VERSION 5.7 ;
  NOWIREEXTENSIONATPIN ON ;
  DIVIDERCHAR "/" ;
  BUSBITCHARS "[]" ;
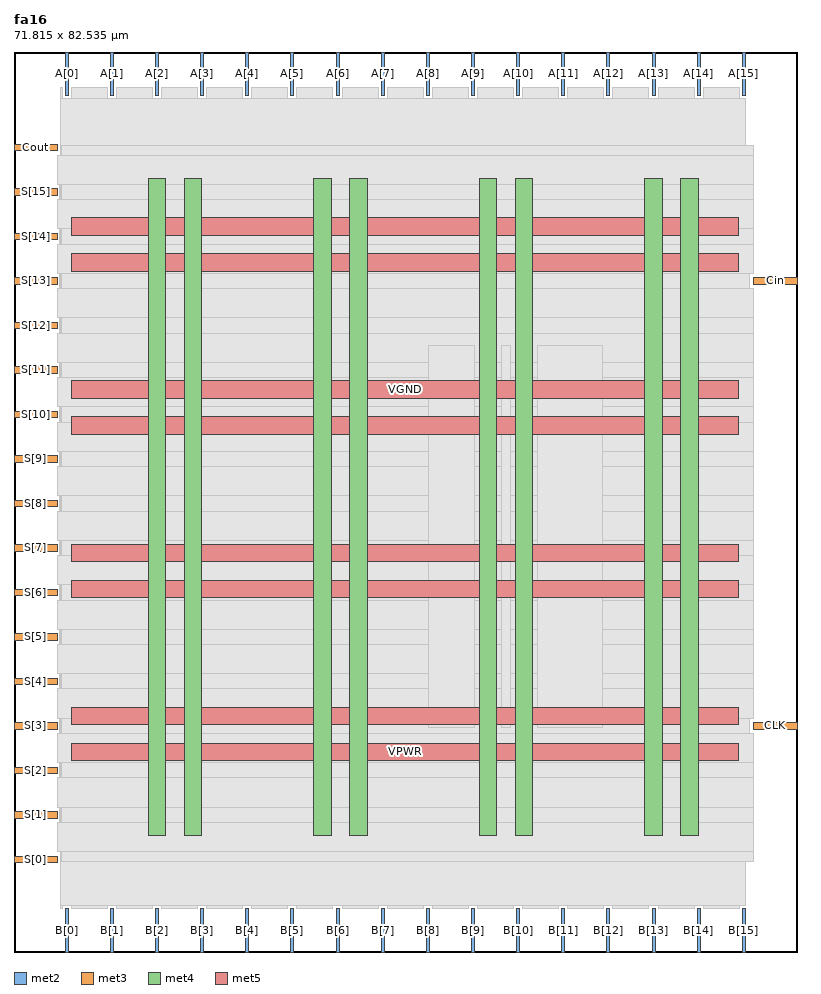
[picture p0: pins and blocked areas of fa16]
MACRO fa16
  CLASS BLOCK ;
  FOREIGN fa16 ;
  ORIGIN 0.000 0.000 ;
  SIZE 71.815 BY 82.535 ;
  PIN A[0]
    DIRECTION INPUT ;
    USE SIGNAL ;
    ANTENNAGATEAREA 0.196500 ;
    PORT
      LAYER met2 ;
        RECT 4.690 78.535 4.970 82.535 ;
    END
  END A[0]
  PIN A[10]
    DIRECTION INPUT ;
    USE SIGNAL ;
    ANTENNAGATEAREA 0.196500 ;
    PORT
      LAYER met2 ;
        RECT 46.090 78.535 46.370 82.535 ;
    END
  END A[10]
  PIN A[11]
    DIRECTION INPUT ;
    USE SIGNAL ;
    ANTENNAGATEAREA 0.196500 ;
    PORT
      LAYER met2 ;
        RECT 50.230 78.535 50.510 82.535 ;
    END
  END A[11]
  PIN A[12]
    DIRECTION INPUT ;
    USE SIGNAL ;
    ANTENNAGATEAREA 0.196500 ;
    PORT
      LAYER met2 ;
        RECT 54.370 78.535 54.650 82.535 ;
    END
  END A[12]
  PIN A[13]
    DIRECTION INPUT ;
    USE SIGNAL ;
    ANTENNAGATEAREA 0.196500 ;
    PORT
      LAYER met2 ;
        RECT 58.510 78.535 58.790 82.535 ;
    END
  END A[13]
  PIN A[14]
    DIRECTION INPUT ;
    USE SIGNAL ;
    ANTENNAGATEAREA 0.196500 ;
    PORT
      LAYER met2 ;
        RECT 62.650 78.535 62.930 82.535 ;
    END
  END A[14]
  PIN A[15]
    DIRECTION INPUT ;
    USE SIGNAL ;
    ANTENNAGATEAREA 0.196500 ;
    PORT
      LAYER met2 ;
        RECT 66.790 78.535 67.070 82.535 ;
    END
  END A[15]
  PIN A[1]
    DIRECTION INPUT ;
    USE SIGNAL ;
    ANTENNAGATEAREA 0.196500 ;
    PORT
      LAYER met2 ;
        RECT 8.830 78.535 9.110 82.535 ;
    END
  END A[1]
  PIN A[2]
    DIRECTION INPUT ;
    USE SIGNAL ;
    ANTENNAGATEAREA 0.196500 ;
    PORT
      LAYER met2 ;
        RECT 12.970 78.535 13.250 82.535 ;
    END
  END A[2]
  PIN A[3]
    DIRECTION INPUT ;
    USE SIGNAL ;
    ANTENNAGATEAREA 0.196500 ;
    PORT
      LAYER met2 ;
        RECT 17.110 78.535 17.390 82.535 ;
    END
  END A[3]
  PIN A[4]
    DIRECTION INPUT ;
    USE SIGNAL ;
    ANTENNAGATEAREA 0.196500 ;
    PORT
      LAYER met2 ;
        RECT 21.250 78.535 21.530 82.535 ;
    END
  END A[4]
  PIN A[5]
    DIRECTION INPUT ;
    USE SIGNAL ;
    ANTENNAGATEAREA 0.196500 ;
    PORT
      LAYER met2 ;
        RECT 25.390 78.535 25.670 82.535 ;
    END
  END A[5]
  PIN A[6]
    DIRECTION INPUT ;
    USE SIGNAL ;
    ANTENNAGATEAREA 0.196500 ;
    PORT
      LAYER met2 ;
        RECT 29.530 78.535 29.810 82.535 ;
    END
  END A[6]
  PIN A[7]
    DIRECTION INPUT ;
    USE SIGNAL ;
    ANTENNAGATEAREA 0.196500 ;
    PORT
      LAYER met2 ;
        RECT 33.670 78.535 33.950 82.535 ;
    END
  END A[7]
  PIN A[8]
    DIRECTION INPUT ;
    USE SIGNAL ;
    ANTENNAGATEAREA 0.196500 ;
    PORT
      LAYER met2 ;
        RECT 37.810 78.535 38.090 82.535 ;
    END
  END A[8]
  PIN A[9]
    DIRECTION INPUT ;
    USE SIGNAL ;
    ANTENNAGATEAREA 0.196500 ;
    PORT
      LAYER met2 ;
        RECT 41.950 78.535 42.230 82.535 ;
    END
  END A[9]
  PIN B[0]
    DIRECTION INPUT ;
    USE SIGNAL ;
    ANTENNAGATEAREA 0.196500 ;
    PORT
      LAYER met2 ;
        RECT 4.690 0.000 4.970 4.000 ;
    END
  END B[0]
  PIN B[10]
    DIRECTION INPUT ;
    USE SIGNAL ;
    ANTENNAGATEAREA 0.196500 ;
    PORT
      LAYER met2 ;
        RECT 46.090 0.000 46.370 4.000 ;
    END
  END B[10]
  PIN B[11]
    DIRECTION INPUT ;
    USE SIGNAL ;
    ANTENNAGATEAREA 0.196500 ;
    PORT
      LAYER met2 ;
        RECT 50.230 0.000 50.510 4.000 ;
    END
  END B[11]
  PIN B[12]
    DIRECTION INPUT ;
    USE SIGNAL ;
    ANTENNAGATEAREA 0.196500 ;
    PORT
      LAYER met2 ;
        RECT 54.370 0.000 54.650 4.000 ;
    END
  END B[12]
  PIN B[13]
    DIRECTION INPUT ;
    USE SIGNAL ;
    ANTENNAGATEAREA 0.196500 ;
    PORT
      LAYER met2 ;
        RECT 58.510 0.000 58.790 4.000 ;
    END
  END B[13]
  PIN B[14]
    DIRECTION INPUT ;
    USE SIGNAL ;
    ANTENNAGATEAREA 0.196500 ;
    PORT
      LAYER met2 ;
        RECT 62.650 0.000 62.930 4.000 ;
    END
  END B[14]
  PIN B[15]
    DIRECTION INPUT ;
    USE SIGNAL ;
    ANTENNAGATEAREA 0.196500 ;
    PORT
      LAYER met2 ;
        RECT 66.790 0.000 67.070 4.000 ;
    END
  END B[15]
  PIN B[1]
    DIRECTION INPUT ;
    USE SIGNAL ;
    ANTENNAGATEAREA 0.196500 ;
    PORT
      LAYER met2 ;
        RECT 8.830 0.000 9.110 4.000 ;
    END
  END B[1]
  PIN B[2]
    DIRECTION INPUT ;
    USE SIGNAL ;
    ANTENNAGATEAREA 0.196500 ;
    PORT
      LAYER met2 ;
        RECT 12.970 0.000 13.250 4.000 ;
    END
  END B[2]
  PIN B[3]
    DIRECTION INPUT ;
    USE SIGNAL ;
    ANTENNAGATEAREA 0.196500 ;
    PORT
      LAYER met2 ;
        RECT 17.110 0.000 17.390 4.000 ;
    END
  END B[3]
  PIN B[4]
    DIRECTION INPUT ;
    USE SIGNAL ;
    ANTENNAGATEAREA 0.196500 ;
    PORT
      LAYER met2 ;
        RECT 21.250 0.000 21.530 4.000 ;
    END
  END B[4]
  PIN B[5]
    DIRECTION INPUT ;
    USE SIGNAL ;
    ANTENNAGATEAREA 0.196500 ;
    PORT
      LAYER met2 ;
        RECT 25.390 0.000 25.670 4.000 ;
    END
  END B[5]
  PIN B[6]
    DIRECTION INPUT ;
    USE SIGNAL ;
    ANTENNAGATEAREA 0.196500 ;
    PORT
      LAYER met2 ;
        RECT 29.530 0.000 29.810 4.000 ;
    END
  END B[6]
  PIN B[7]
    DIRECTION INPUT ;
    USE SIGNAL ;
    ANTENNAGATEAREA 0.196500 ;
    PORT
      LAYER met2 ;
        RECT 33.670 0.000 33.950 4.000 ;
    END
  END B[7]
  PIN B[8]
    DIRECTION INPUT ;
    USE SIGNAL ;
    ANTENNAGATEAREA 0.196500 ;
    PORT
      LAYER met2 ;
        RECT 37.810 0.000 38.090 4.000 ;
    END
  END B[8]
  PIN B[9]
    DIRECTION INPUT ;
    USE SIGNAL ;
    ANTENNAGATEAREA 0.196500 ;
    PORT
      LAYER met2 ;
        RECT 41.950 0.000 42.230 4.000 ;
    END
  END B[9]
  PIN CLK
    DIRECTION INPUT ;
    USE SIGNAL ;
    ANTENNAGATEAREA 0.852000 ;
    PORT
      LAYER met3 ;
        RECT 67.815 20.440 71.815 21.040 ;
    END
  END CLK
  PIN Cin
    DIRECTION INPUT ;
    USE SIGNAL ;
    ANTENNAGATEAREA 0.196500 ;
    PORT
      LAYER met3 ;
        RECT 67.815 61.240 71.815 61.840 ;
    END
  END Cin
  PIN Cout
    DIRECTION OUTPUT ;
    USE SIGNAL ;
    ANTENNADIFFAREA 0.340600 ;
    PORT
      LAYER met3 ;
        RECT 0.000 73.480 4.000 74.080 ;
    END
  END Cout
  PIN S[0]
    DIRECTION OUTPUT ;
    USE SIGNAL ;
    ANTENNADIFFAREA 0.340600 ;
    PORT
      LAYER met3 ;
        RECT 0.000 8.200 4.000 8.800 ;
    END
  END S[0]
  PIN S[10]
    DIRECTION OUTPUT ;
    USE SIGNAL ;
    ANTENNADIFFAREA 0.340600 ;
    PORT
      LAYER met3 ;
        RECT 0.000 49.000 4.000 49.600 ;
    END
  END S[10]
  PIN S[11]
    DIRECTION OUTPUT ;
    USE SIGNAL ;
    ANTENNADIFFAREA 0.340600 ;
    PORT
      LAYER met3 ;
        RECT 0.000 53.080 4.000 53.680 ;
    END
  END S[11]
  PIN S[12]
    DIRECTION OUTPUT ;
    USE SIGNAL ;
    ANTENNADIFFAREA 0.340600 ;
    PORT
      LAYER met3 ;
        RECT 0.000 57.160 4.000 57.760 ;
    END
  END S[12]
  PIN S[13]
    DIRECTION OUTPUT ;
    USE SIGNAL ;
    ANTENNADIFFAREA 0.340600 ;
    PORT
      LAYER met3 ;
        RECT 0.000 61.240 4.000 61.840 ;
    END
  END S[13]
  PIN S[14]
    DIRECTION OUTPUT ;
    USE SIGNAL ;
    ANTENNADIFFAREA 0.340600 ;
    PORT
      LAYER met3 ;
        RECT 0.000 65.320 4.000 65.920 ;
    END
  END S[14]
  PIN S[15]
    DIRECTION OUTPUT ;
    USE SIGNAL ;
    ANTENNADIFFAREA 0.340600 ;
    PORT
      LAYER met3 ;
        RECT 0.000 69.400 4.000 70.000 ;
    END
  END S[15]
  PIN S[1]
    DIRECTION OUTPUT ;
    USE SIGNAL ;
    ANTENNADIFFAREA 0.340600 ;
    PORT
      LAYER met3 ;
        RECT 0.000 12.280 4.000 12.880 ;
    END
  END S[1]
  PIN S[2]
    DIRECTION OUTPUT ;
    USE SIGNAL ;
    ANTENNADIFFAREA 0.340600 ;
    PORT
      LAYER met3 ;
        RECT 0.000 16.360 4.000 16.960 ;
    END
  END S[2]
  PIN S[3]
    DIRECTION OUTPUT ;
    USE SIGNAL ;
    ANTENNADIFFAREA 0.340600 ;
    PORT
      LAYER met3 ;
        RECT 0.000 20.440 4.000 21.040 ;
    END
  END S[3]
  PIN S[4]
    DIRECTION OUTPUT ;
    USE SIGNAL ;
    ANTENNADIFFAREA 0.340600 ;
    PORT
      LAYER met3 ;
        RECT 0.000 24.520 4.000 25.120 ;
    END
  END S[4]
  PIN S[5]
    DIRECTION OUTPUT ;
    USE SIGNAL ;
    ANTENNADIFFAREA 0.340600 ;
    PORT
      LAYER met3 ;
        RECT 0.000 28.600 4.000 29.200 ;
    END
  END S[5]
  PIN S[6]
    DIRECTION OUTPUT ;
    USE SIGNAL ;
    ANTENNADIFFAREA 0.340600 ;
    PORT
      LAYER met3 ;
        RECT 0.000 32.680 4.000 33.280 ;
    END
  END S[6]
  PIN S[7]
    DIRECTION OUTPUT ;
    USE SIGNAL ;
    ANTENNADIFFAREA 0.340600 ;
    PORT
      LAYER met3 ;
        RECT 0.000 36.760 4.000 37.360 ;
    END
  END S[7]
  PIN S[8]
    DIRECTION OUTPUT ;
    USE SIGNAL ;
    ANTENNADIFFAREA 0.340600 ;
    PORT
      LAYER met3 ;
        RECT 0.000 40.840 4.000 41.440 ;
    END
  END S[8]
  PIN S[9]
    DIRECTION OUTPUT ;
    USE SIGNAL ;
    ANTENNADIFFAREA 0.340600 ;
    PORT
      LAYER met3 ;
        RECT 0.000 44.920 4.000 45.520 ;
    END
  END S[9]
  PIN VGND
    DIRECTION INOUT ;
    USE GROUND ;
    PORT
      LAYER met4 ;
        RECT 15.610 10.640 17.210 70.960 ;
    END
    PORT
      LAYER met4 ;
        RECT 30.790 10.640 32.390 70.960 ;
    END
    PORT
      LAYER met4 ;
        RECT 45.970 10.640 47.570 70.960 ;
    END
    PORT
      LAYER met4 ;
        RECT 61.150 10.640 62.750 70.960 ;
    END
    PORT
      LAYER met5 ;
        RECT 5.280 20.855 66.480 22.455 ;
    END
    PORT
      LAYER met5 ;
        RECT 5.280 35.810 66.480 37.410 ;
    END
    PORT
      LAYER met5 ;
        RECT 5.280 50.765 66.480 52.365 ;
    END
    PORT
      LAYER met5 ;
        RECT 5.280 65.720 66.480 67.320 ;
    END
  END VGND
  PIN VPWR
    DIRECTION INOUT ;
    USE POWER ;
    PORT
      LAYER met4 ;
        RECT 12.310 10.640 13.910 70.960 ;
    END
    PORT
      LAYER met4 ;
        RECT 27.490 10.640 29.090 70.960 ;
    END
    PORT
      LAYER met4 ;
        RECT 42.670 10.640 44.270 70.960 ;
    END
    PORT
      LAYER met4 ;
        RECT 57.850 10.640 59.450 70.960 ;
    END
    PORT
      LAYER met5 ;
        RECT 5.280 17.555 66.480 19.155 ;
    END
    PORT
      LAYER met5 ;
        RECT 5.280 32.510 66.480 34.110 ;
    END
    PORT
      LAYER met5 ;
        RECT 5.280 47.465 66.480 49.065 ;
    END
    PORT
      LAYER met5 ;
        RECT 5.280 62.420 66.480 64.020 ;
    END
  END VPWR
  OBS
      LAYER nwell ;
        RECT 5.330 10.795 66.430 70.805 ;
      LAYER li1 ;
        RECT 5.520 10.795 66.240 70.805 ;
      LAYER met1 ;
        RECT 4.210 10.640 67.090 71.360 ;
      LAYER met2 ;
        RECT 4.230 78.255 4.410 79.290 ;
        RECT 5.250 78.255 8.550 79.290 ;
        RECT 9.390 78.255 12.690 79.290 ;
        RECT 13.530 78.255 16.830 79.290 ;
        RECT 17.670 78.255 20.970 79.290 ;
        RECT 21.810 78.255 25.110 79.290 ;
        RECT 25.950 78.255 29.250 79.290 ;
        RECT 30.090 78.255 33.390 79.290 ;
        RECT 34.230 78.255 37.530 79.290 ;
        RECT 38.370 78.255 41.670 79.290 ;
        RECT 42.510 78.255 45.810 79.290 ;
        RECT 46.650 78.255 49.950 79.290 ;
        RECT 50.790 78.255 54.090 79.290 ;
        RECT 54.930 78.255 58.230 79.290 ;
        RECT 59.070 78.255 62.370 79.290 ;
        RECT 63.210 78.255 66.510 79.290 ;
        RECT 4.230 4.280 67.060 78.255 ;
        RECT 4.230 4.000 4.410 4.280 ;
        RECT 5.250 4.000 8.550 4.280 ;
        RECT 9.390 4.000 12.690 4.280 ;
        RECT 13.530 4.000 16.830 4.280 ;
        RECT 17.670 4.000 20.970 4.280 ;
        RECT 21.810 4.000 25.110 4.280 ;
        RECT 25.950 4.000 29.250 4.280 ;
        RECT 30.090 4.000 33.390 4.280 ;
        RECT 34.230 4.000 37.530 4.280 ;
        RECT 38.370 4.000 41.670 4.280 ;
        RECT 42.510 4.000 45.810 4.280 ;
        RECT 46.650 4.000 49.950 4.280 ;
        RECT 50.790 4.000 54.090 4.280 ;
        RECT 54.930 4.000 58.230 4.280 ;
        RECT 59.070 4.000 62.370 4.280 ;
        RECT 63.210 4.000 66.510 4.280 ;
      LAYER met3 ;
        RECT 4.400 73.080 67.815 73.945 ;
        RECT 3.990 70.400 67.815 73.080 ;
        RECT 4.400 69.000 67.815 70.400 ;
        RECT 3.990 66.320 67.815 69.000 ;
        RECT 4.400 64.920 67.815 66.320 ;
        RECT 3.990 62.240 67.815 64.920 ;
        RECT 4.400 60.840 67.415 62.240 ;
        RECT 3.990 58.160 67.815 60.840 ;
        RECT 4.400 56.760 67.815 58.160 ;
        RECT 3.990 54.080 67.815 56.760 ;
        RECT 4.400 52.680 67.815 54.080 ;
        RECT 3.990 50.000 67.815 52.680 ;
        RECT 4.400 48.600 67.815 50.000 ;
        RECT 3.990 45.920 67.815 48.600 ;
        RECT 4.400 44.520 67.815 45.920 ;
        RECT 3.990 41.840 67.815 44.520 ;
        RECT 4.400 40.440 67.815 41.840 ;
        RECT 3.990 37.760 67.815 40.440 ;
        RECT 4.400 36.360 67.815 37.760 ;
        RECT 3.990 33.680 67.815 36.360 ;
        RECT 4.400 32.280 67.815 33.680 ;
        RECT 3.990 29.600 67.815 32.280 ;
        RECT 4.400 28.200 67.815 29.600 ;
        RECT 3.990 25.520 67.815 28.200 ;
        RECT 4.400 24.120 67.815 25.520 ;
        RECT 3.990 21.440 67.815 24.120 ;
        RECT 4.400 20.040 67.415 21.440 ;
        RECT 3.990 17.360 67.815 20.040 ;
        RECT 4.400 15.960 67.815 17.360 ;
        RECT 3.990 13.280 67.815 15.960 ;
        RECT 4.400 11.880 67.815 13.280 ;
        RECT 3.990 9.200 67.815 11.880 ;
        RECT 4.400 8.335 67.815 9.200 ;
      LAYER met4 ;
        RECT 38.015 20.575 42.270 55.585 ;
        RECT 44.670 20.575 45.570 55.585 ;
        RECT 47.970 20.575 53.985 55.585 ;
  END
END fa16
END LIBRARY

